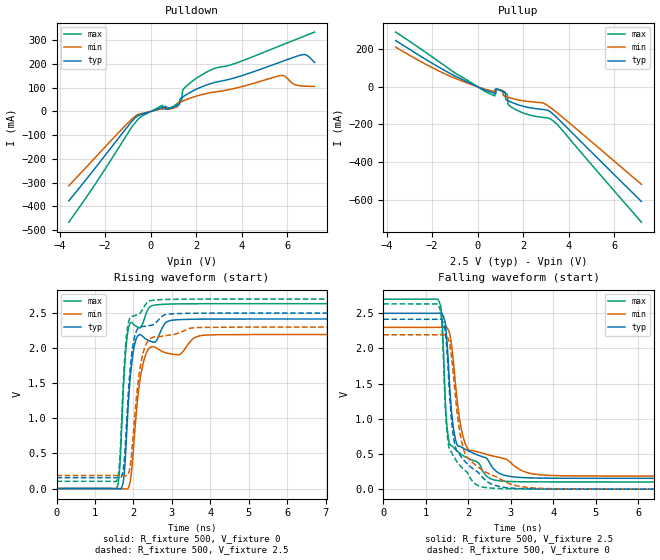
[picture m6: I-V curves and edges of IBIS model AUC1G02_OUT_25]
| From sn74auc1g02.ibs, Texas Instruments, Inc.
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[Model]   AUC1G02_OUT_25
Model_type  Output
Vref =   0
Rref =   500
Cref =   30p
Vmeas =   1.25
| variable   typ   min   max
C_comp   4.93pF   0.39pF   11.12pF
| C_pullup   5.22pF   0.39pF   11.12pF
| C_pulldown   4.64pF   0.40pF   6.60pF
[Temperature Range]   40   100   -40
| Ambient temperature   25   85   -40
[Voltage range]   2.5   2.3   2.7
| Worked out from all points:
|   slope of the pulldown table from 0 to 0.375 V, typ, clamps not added: 30.9 ohm
|   slope of the pullup table from 0 to 0.375 V, typ, clamps not added: 19.1 ohm
|   rising waveform, R_fixture 500, V_fixture 0: 20-80 % time 196ps typ, 259ps min, 158ps max; typ from 0 V to 2.42 V
|   falling waveform, R_fixture 500, V_fixture 2.5: 20-80 % time 237ps typ, 315ps min, 197ps max; typ from 2.5 V to 0.154 V
|   rising waveform, R_fixture 500, V_fixture 2.5: 20-80 % time 194ps typ, 257ps min, 157ps max; typ from 0.154 V to 2.5 V
|   falling waveform, R_fixture 500, V_fixture 0: 20-80 % time 304ps typ, 370ps min, 202ps max; typ from 2.42 V to 0 V
[Pulldown]
| AUC1G02_OUT_25
|   Voltage   I(typ)   I(min)   I(max)
-3.6V     -377.3mA   -313.6mA   -467.3mA
-450mV    -13.55mA   -9.199mA   -23.42mA
515mV     17.02mA    12.57mA    25.99mA
1.025V    18.9mA     15.4mA     23.61mA
1.27V     30.1mA     38.43mA    41.47mA
1.37V     59.42mA    42.49mA    49.07mA
1.395V    60.94mA    43.5mA     85.27mA
1.48V     66.06mA    46.86mA    98.94mA
2.54V     114.8mA    77.9mA     170.7mA
5.695V    208.5mA    151.4mA    277.9mA
6.74V     240.5mA    107.1mA    317.9mA
7.2V      207mA      105.8mA    335.2mA
[Pullup]
| AUC1G02_OUT_25
|   Voltage   I(typ)   I(min)   I(max)
-3.6V     246.2mA    211mA      291.3mA
290mV     -15.56mA   -11.38mA   -21.64mA
750mV     -34.5mA    -24.9mA    -48.13mA
770mV     -35.18mA   -25.36mA   -13.07mA
1.115V    -23.95mA   -20.34mA   -27.78mA
1.215V    -28.93mA   -50.57mA   -34.8mA
1.235V    -63.85mA   -51.41mA   -36.2mA
1.295V    -71.17mA   -53.86mA   -40.35mA
1.34V     -74.13mA   -55.63mA   -92.46mA
1.59V     -87.28mA   -64.24mA   -115.7mA
3.28V     -141.4mA   -117.9mA   -177.8mA
7.2V      -610.5mA   -519.3mA   -720.6mA
[Ramp]
| AUC1G02_OUT_25
| variable   typ   min   max
dV/dt_r   1.46/1.99E-10   1.32/2.61E-10   1.58/1.59E-10
dV/dt_f   1.41/2.39E-10   1.28/3.16E-10   1.56/1.98E-10
R_load = 500
[Rising Waveform]
| AUC1G02_OUT_25
R_fixture =   500
C_fixture =   0
L_fixture =   0
V_fixture =   0
V_fixture_min = 0
V_fixture_max = 0
|   Time   V(typ)   V(min)   V(max)
0s        8.552nV    24.69nV    1.796nV
1.56ns    -2.155mV   -44.43uV   506.3uV
1.64ns    -6.797mV   -188.6uV   261mV
1.735ns   92.22mV    -3.3mV     1.391V
1.87ns    1.234V     13.09mV    2.281V
2.08ns    2.143V     1.114V     2.309V
2.275ns   2.151V     1.833V     2.404V
2.525ns   2.085V     2.021V     2.612V
3.345ns   2.41V      1.996V     2.633V
24.99ns   2.416V     2.195V     2.634V
[Falling Waveform]
| AUC1G02_OUT_25
R_fixture =   500
C_fixture =   0
L_fixture =   0
V_fixture =   2.5
V_fixture_min = 2.3
V_fixture_max = 2.7
|   Time   V(typ)   V(min)   V(max)
0s        2.5V       2.3V       2.7V
1.285ns   2.501V     2.3V       2.699V
1.38ns    2.497V     2.303V     2.421V
1.455ns   2.372V     2.312V     1.314V
1.555ns   1.53V      2.226V     648.9mV
1.695ns   717.2mV    1.516V     564.8mV
1.93ns    567.5mV    643.2mV    458.7mV
2.67ns    248.5mV    458.6mV    124.1mV
4.21ns    155.1mV    190.2mV    102.8mV
24.99ns   154.5mV    186.3mV    102.6mV
[Rising Waveform]
| AUC1G02_OUT_25
R_fixture =   500
C_fixture =   0
L_fixture =   0
V_fixture =   2.5
V_fixture_min = 2.3
V_fixture_max = 2.7
|   Time   V(typ)   V(min)   V(max)
0s        154.5mV    186.3mV    102.6mV
1.56ns    153mV      186.3mV    104.4mV
1.64ns    149.6mV    186.2mV    380.2mV
1.73ns    246.1mV    184.2mV    1.436V
1.86ns    1.304V     198.6mV    2.334V
1.935ns   1.817V     400.4mV    2.449V
2.05ns    2.204V     1.136V     2.467V
2.23ns    2.308V     1.884V     2.544V
2.45ns    2.325V     2.142V     2.678V
24.99ns   2.5V       2.3V       2.7V
[Falling Waveform]
| AUC1G02_OUT_25
R_fixture =   500
C_fixture =   0
L_fixture =   0
V_fixture =   0
V_fixture_min = 0
V_fixture_max = 0
|   Time   V(typ)   V(min)   V(max)
0s        2.416V     2.195V     2.634V
1.285ns   2.415V     2.195V     2.629V
1.38ns    2.405V     2.195V     2.329V
1.455ns   2.26V      2.196V     1.21V
1.545ns   1.482V     2.105V     595.5mV
1.675ns   661.2mV    1.452V     445mV
1.875ns   427.7mV    597.5mV    292.3mV
2.365ns   148.9mV    259.4mV    27.2mV
4.11ns    726.1uV    4.32mV     171uV
24.99ns   17.46uV    1.178uV    8.082uV
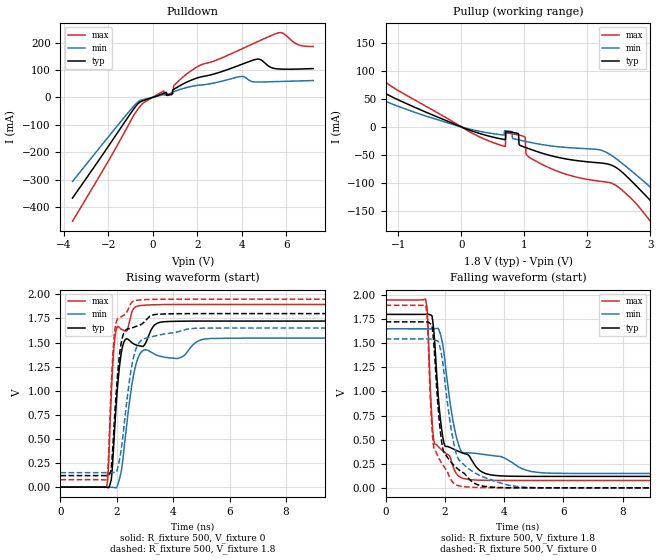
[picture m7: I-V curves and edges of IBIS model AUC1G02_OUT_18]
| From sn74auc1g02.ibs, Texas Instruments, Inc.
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[Model]   AUC1G02_OUT_18
Model_type  Output
Vref =   0
Rref =   1000
Cref =   30p
Vmeas =   0.9
| variable   typ   min   max
C_comp   5.30pF   0.57pF   7.93pF
| C_pullup   4.83pF   0.57pF   7.93pF
| C_pulldown   5.78pF   2.98pF   7.79pF
[Temperature Range]   40   100   -40
| Ambient temperature   25   85   -40
[Voltage range]   1.8   1.65   1.95
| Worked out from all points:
|   slope of the pulldown table from 0 to 0.27 V, typ, clamps not added: 34.4 ohm
|   slope of the pullup table from 0 to 0.27 V, typ, clamps not added: 24.6 ohm
|   rising waveform, R_fixture 500, V_fixture 0: 20-80 % time 279ps typ, 424ps min, 192ps max; typ from 0 V to 1.72 V
|   falling waveform, R_fixture 500, V_fixture 1.8: 20-80 % time 311ps typ, 471ps min, 253ps max; typ from 1.8 V to 0.119 V
|   rising waveform, R_fixture 500, V_fixture 1.8: 20-80 % time 271ps typ, 411ps min, 185ps max; typ from 0.119 V to 1.8 V
|   falling waveform, R_fixture 500, V_fixture 0: 20-80 % time 374ps typ, 486ps min, 249ps max; typ from 1.72 V to 0 V
[Pulldown]
| AUC1G02_OUT_18
|   Voltage   I(typ)   I(min)   I(max)
-3.6V     -367.3mA   -306.5mA   -451.8mA
-840mV    -41.05mA   -31.3mA    -64.3mA
-415mV    -11.62mA   -7.635mA   -20.14mA
495mV     14.95mA    10.62mA    23.51mA
885mV     12.29mA    19.09mA    15.87mA
925mV     28.57mA    20.19mA    16.9mA
960mV     30.15mA    21.18mA    44.34mA
2.04V     71.84mA    43.97mA    113.3mA
3.92V     118.2mA    75.81mA    173.7mA
4.62V     138.3mA    55.96mA    199.9mA
5.58V     103.9mA    57.6mA     233.8mA
7.2V      105mA      61.31mA    185.3mA
[Pullup]
| AUC1G02_OUT_18
|   Voltage   I(typ)   I(min)   I(max)
-3.6V     220.3mA    181.9mA    264.7mA
-2.44V    138.5mA    110.5mA    175.8mA
180mV     -7.622mA   -5.122mA   -11.6mA
695mV     -22.64mA   -6.828mA   -34.84mA
705mV     -8.169mA   -6.943mA   -10.57mA
905mV     -11.83mA   -22.82mA   -14.13mA
970mV     -34.54mA   -24.44mA   -16.12mA
1.11V     -40.27mA   -27.85mA   -56.21mA
2.24V     -64.51mA   -42.18mA   -97.18mA
3.135V    -146.9mA   -120.3mA   -187.2mA
3.975V    -247.4mA   -204.7mA   -306.6mA
7.2V      -630.7mA   -535mA     -754.9mA
[Ramp]
| AUC1G02_OUT_18
| variable   typ   min   max
dV/dt_r   1.04/2.81E-10   0.93/4.33E-10   1.14/1.94E-10
dV/dt_f   1.01/3.13E-10   0.90/4.79E-10   1.13/2.47E-10
R_load = 500
[Rising Waveform]
| AUC1G02_OUT_18
R_fixture =   500
C_fixture =   0
L_fixture =   0
V_fixture =   0
V_fixture_min = 0
V_fixture_max = 0
|   Time   V(typ)   V(min)   V(max)
0s        6.473nV    21.42nV    1.057nV
1.635ns   -1.692mV   272uV      -213.1uV
1.7ns     -7.353mV   395.4uV    191.9mV
1.805ns   81.56mV    -1.199mV   973.5mV
1.955ns   758.2mV    -6.809mV   1.6V
2.23ns    1.488V     327.3mV    1.627V
2.735ns   1.47V      1.327V     1.878V
3.865ns   1.718V     1.341V     1.894V
5.365ns   1.722V     1.542V     1.895V
24.99ns   1.722V     1.546V     1.894V
[Falling Waveform]
| AUC1G02_OUT_18
R_fixture =   500
C_fixture =   0
L_fixture =   0
V_fixture =   1.8
V_fixture_min = 1.65
V_fixture_max = 1.95
|   Time   V(typ)   V(min)   V(max)
0s        1.8V       1.65V      1.95V
1.345ns   1.801V     1.65V      1.956V
1.405ns   1.802V     1.65V      1.828V
1.535ns   1.792V     1.65V      859.6mV
1.64ns    1.576V     1.651V     464.7mV
1.97ns    463mV      1.395V     372.7mV
2.315ns   398.8mV    628.6mV    189.2mV
2.65ns    356mV      363.1mV    95.62mV
4.035ns   122.2mV    306.9mV    76.53mV
24.99ns   118.7mV    149.7mV    76.31mV
[Rising Waveform]
| AUC1G02_OUT_18
R_fixture =   500
C_fixture =   0
L_fixture =   0
V_fixture =   1.8
V_fixture_min = 1.65
V_fixture_max = 1.95
|   Time   V(typ)   V(min)   V(max)
0s        118.7mV    149.7mV    76.3mV
1.635ns   117.5mV    149.8mV    78.99mV
1.695ns   118.2mV    149.9mV    258.2mV
1.79ns    172.4mV    150.6mV    969.7mV
1.945ns   842.8mV    153.5mV    1.663V
2.19ns    1.545V     466.1mV    1.773V
2.45ns    1.645V     1.111V     1.877V
2.645ns   1.663V     1.406V     1.935V
4.8ns     1.8V       1.648V     1.95V
24.99ns   1.8V       1.65V      1.95V
[Falling Waveform]
| AUC1G02_OUT_18
R_fixture =   500
C_fixture =   0
L_fixture =   0
V_fixture =   0
V_fixture_min = 0
V_fixture_max = 0
|   Time   V(typ)   V(min)   V(max)
0s        1.722V     1.546V     1.894V
1.345ns   1.722V     1.545V     1.894V
1.405ns   1.722V     1.545V     1.754V
1.525ns   1.7V       1.544V     825mV
1.62ns    1.516V     1.538V     426.8mV
1.925ns   412.6mV    1.304V     239.5mV
2.225ns   260.7mV    587.3mV    74.68mV
2.485ns   184.2mV    287.1mV    19.95mV
4.825ns   219.2uV    4.962mV    -80.61uV
24.99ns   20.57uV    2.16uV     9.128uV
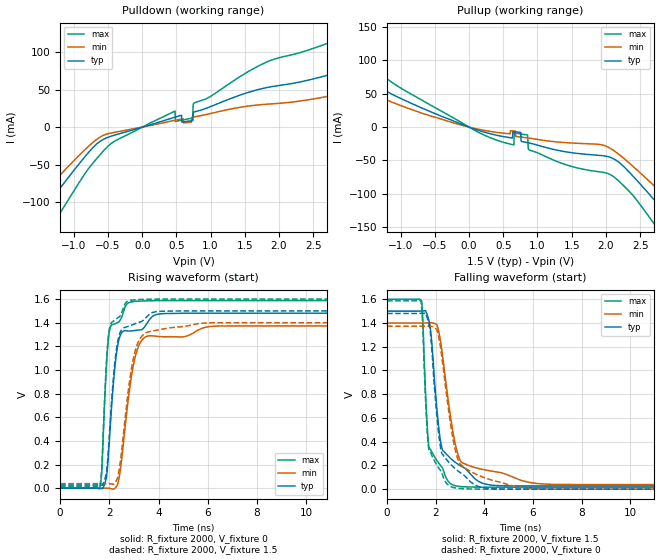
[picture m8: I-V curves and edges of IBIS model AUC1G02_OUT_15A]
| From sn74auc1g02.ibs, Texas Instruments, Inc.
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[Model]   AUC1G02_OUT_15A
Model_type  Output
Vref =   0
Rref =   2000
Cref =   15p
Vmeas =   0.75
| variable   typ   min   max
C_comp   6.58pF   0.06pF   14.96pF
| C_pullup   4.77pF   0.06pF   9.14pF
| C_pulldown   8.38pF   2.09pF   14.96pF
[Temperature Range]   40   100   -40
| Ambient temperature   25   85   -40
[Voltage range]   1.5   1.4   1.6
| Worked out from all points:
|   slope of the pulldown table from 0 to 0.225 V, typ, clamps not added: 36.6 ohm
|   slope of the pullup table from 0 to 0.225 V, typ, clamps not added: 29.5 ohm
|   rising waveform, R_fixture 2000, V_fixture 0: 20-80 % time 355ps typ, 520ps min, 237ps max; typ from 0 V to 1.48 V
|   falling waveform, R_fixture 2000, V_fixture 1.5: 20-80 % time 455ps typ, 607ps min, 287ps max; typ from 1.5 V to 0.027 V
|   rising waveform, R_fixture 2000, V_fixture 1.5: 20-80 % time 351ps typ, 512ps min, 234ps max; typ from 0.027 V to 1.5 V
|   falling waveform, R_fixture 2000, V_fixture 0: 20-80 % time 428ps typ, 615ps min, 282ps max; typ from 1.48 V to 0 V
[Pulldown]
| AUC1G02_OUT_15A
|   Voltage   I(typ)   I(min)   I(max)
-3.6V     -362.7mA   -303.6mA   -444.4mA
-2.14V    -192.5mA   -156.8mA   -246.4mA
-1.825V   -155.4mA   -125.4mA   -203.1mA
-1.36V    -100.2mA   -79.41mA   -137.7mA
-405mV    -10.71mA   -6.927mA   -18.81mA
480mV     13.33mA    9.224mA    21.44mA
485mV     13.46mA    9.315mA    7.619mA
735mV     8.725mA    13.4mA     12.06mA
755mV     20.22mA    13.7mA     32.02mA
1.69V     50.1mA     29.63mA    81.31mA
3.34V     86.08mA    49.9mA     134.3mA
7.2V      80.61mA    45.5mA     141.2mA
[Pullup]
| AUC1G02_OUT_15A
|   Voltage   I(typ)   I(min)   I(max)
-3.6V     206.9mA    155.1mA    250.9mA
-2.745V   148.8mA    117.7mA    187.1mA
-2.3V     119.4mA    93.54mA    153.8mA
115mV     -4.163mA   -2.727mA   -6.621mA
650mV     -6.722mA   -5.655mA   -26.6mA
660mV     -6.84mA    -5.748mA   -8.817mA
855mV     -23.23mA   -16.19mA   -11.7mA
885mV     -23.9mA    -16.64mA   -34.51mA
2.09V     -46.33mA   -33.4mA    -72.65mA
2.735V    -112.2mA   -90.7mA    -149.1mA
3.355V    -185.6mA   -151.9mA   -237.2mA
7.2V      -640.7mA   -543.6mA   -770.5mA
[Ramp]
| AUC1G02_OUT_15A
| variable   typ   min   max
dV/dt_r   0.89/3.58E-10   0.83/5.26E-10   0.96/2.39E-10
dV/dt_f   0.89/4.77E-10   0.82/6.11E-10   0.95/2.87E-10
R_load = 2000
[Rising Waveform]
| AUC1G02_OUT_15A
R_fixture =   2000
C_fixture =   0
L_fixture =   0
V_fixture =   0
V_fixture_min = 0
V_fixture_max = 0
|   Time   V(typ)   V(min)   V(max)
0s        6.138nV    22.63nV    845.8pV
1.605ns   -1.237mV   80.59uV    -4.897mV
1.69ns    -2.471mV   119uV      141.4mV
1.885ns   95.51mV    231.7uV    1.049V
1.995ns   386.2mV    99.07uV    1.318V
2.345ns   1.214V     38.89mV    1.402V
2.835ns   1.33V      859.3mV    1.573V
3.41ns    1.359V     1.271V     1.584V
6.105ns   1.481V     1.368V     1.587V
24.99ns   1.481V     1.373V     1.587V
[Falling Waveform]
| AUC1G02_OUT_15A
R_fixture =   2000
C_fixture =   0
L_fixture =   0
V_fixture =   1.5
V_fixture_min = 1.4
V_fixture_max = 1.6
|   Time   V(typ)   V(min)   V(max)
0s        1.5V       1.4V       1.6V
1.42ns    1.502V     1.4V       1.587V
1.62ns    1.487V     1.401V     652.2mV
1.725ns   1.417V     1.402V     353mV
2.045ns   684.3mV    1.387V     243.1mV
2.21ns    391.2mV    1.232V     196.7mV
2.745ns   235.9mV    440.2mV    32.49mV
3.095ns   188.6mV    221.6mV    20.71mV
6.18ns    27.16mV    47.24mV    16.43mV
24.99ns   27.2mV     38.78mV    16.41mV
[Rising Waveform]
| AUC1G02_OUT_15A
R_fixture =   2000
C_fixture =   0
L_fixture =   0
V_fixture =   1.5
V_fixture_min = 1.4
V_fixture_max = 1.6
|   Time   V(typ)   V(min)   V(max)
0s        27.17mV    38.78mV    16.4mV
1.605ns   26.31mV    38.84mV    12.35mV
1.69ns    25.44mV    38.88mV    164.3mV
1.885ns   138.1mV    38.98mV    1.077V
1.995ns   435.6mV    38.91mV    1.339V
2.325ns   1.225V     82.87mV    1.439V
2.81ns    1.372V     888.6mV    1.587V
3.385ns   1.422V     1.3V       1.597V
5.68ns    1.5V       1.394V     1.6V
24.99ns   1.5V       1.4V       1.6V
[Falling Waveform]
| AUC1G02_OUT_15A
R_fixture =   2000
C_fixture =   0
L_fixture =   0
V_fixture =   0
V_fixture_min = 0
V_fixture_max = 0
|   Time   V(typ)   V(min)   V(max)
0s        1.481V     1.373V     1.587V
1.39ns    1.481V     1.373V     1.591V
1.62ns    1.463V     1.373V     598.4mV
1.71ns    1.398V     1.373V     343.8mV
2.045ns   623mV      1.345V     203.6mV
2.2ns     348.2mV    1.192V     156.8mV
2.7ns     191.9mV    436.3mV    15.5mV
3.24ns    102.4mV    174.6mV    2.696mV
5.685ns   115.9uV    9.469mV    3.293uV
24.99ns   24.12uV    3.304uV    10.3uV
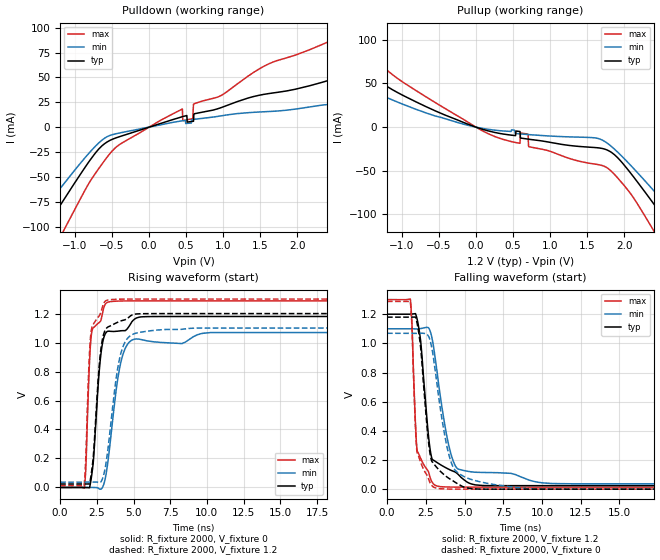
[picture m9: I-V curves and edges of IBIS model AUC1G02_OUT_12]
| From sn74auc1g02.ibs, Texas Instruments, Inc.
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[Model]   AUC1G02_OUT_12
Model_type  Output
Vref =   0
Rref =   2000
Cref =   15p
Vmeas =   0.6
| variable   typ   min   max
C_comp   8.58pF   0.77pF   20.74pF
| C_pullup   6.20pF   0.77pF   15.62pF
| C_pulldown   10.96pF   4.26pF   20.74pF
[Temperature Range]   40   100   -40
| Ambient temperature   25   85   -40
[Voltage range]   1.2   1.1   1.3
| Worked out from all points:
|   slope of the pulldown table from 0 to 0.18 V, typ, clamps not added: 41.7 ohm
|   slope of the pullup table from 0 to 0.18 V, typ, clamps not added: 39.1 ohm
|   rising waveform, R_fixture 2000, V_fixture 0: 20-80 % time 505ps typ, 818ps min, 307ps max; typ from 0 V to 1.18 V
|   falling waveform, R_fixture 2000, V_fixture 1.2: 20-80 % time 587ps typ, 980ps min, 296ps max; typ from 1.2 V to 0.024 V
|   rising waveform, R_fixture 2000, V_fixture 1.2: 20-80 % time 498ps typ, 809ps min, 305ps max; typ from 0.024 V to 1.2 V
|   falling waveform, R_fixture 2000, V_fixture 0: 20-80 % time 593ps typ, 995ps min, 298ps max; typ from 1.18 V to 0 V
[Pulldown]
| AUC1G02_OUT_12
|   Voltage   I(typ)   I(min)   I(max)
-3.6V     -358.1mA   -300.1mA   -438mA
-1.74V    -141.6mA   -114.1mA   -185.6mA
-1.425V   -104.9mA   -83.3mA    -142.2mA
-1.205V   -79.25mA   -62.17mA   -111.4mA
-680mV    -22.07mA   -15.95mA   -41.78mA
-400mV    -9.617mA   -5.913mA   -17.55mA
450mV     10.5mA     6.398mA    18.24mA
590mV     5.848mA    7.731mA    8.546mA
605mV     12.96mA    7.861mA    23.36mA
2.86V     55.95mA    19.1mA     100.7mA
3.425V    44.58mA    20.08mA    119.3mA
7.2V      57.06mA    26.83mA    108mA
[Pullup]
| AUC1G02_OUT_12
|   Voltage   I(typ)   I(min)   I(max)
-3.6V     177mA      42.66mA    237.7mA
-2.43V    116.1mA    56.06mA    152.8mA
-1.99V    89.76mA    64.98mA    121mA
85mV      -2.357mA   -1.386mA   -4.118mA
595mV     -5.009mA   -7.72mA    -18.47mA
700mV     -13.68mA   -8.451mA   -7.891mA
720mV     -13.91mA   -8.58mA    -22.52mA
1.785V    -26.75mA   -19.14mA   -47.45mA
2.43V     -91.29mA   -75.54mA   -122.8mA
2.73V     -126.3mA   -104.6mA   -165.3mA
3.085V    -168.1mA   -139.6mA   -215.3mA
7.2V      -652.5mA   -556.7mA   -783.9mA
[Ramp]
| AUC1G02_OUT_12
| variable   typ   min   max
dV/dt_r   0.71/5.13E-10   0.65/8.28E-10   0.78/3.16E-10
dV/dt_f   0.71/5.97E-10   0.64/9.93E-10   0.77/3.02E-10
R_load = 2000
[Rising Waveform]
| AUC1G02_OUT_12
R_fixture =   2000
C_fixture =   0
L_fixture =   0
V_fixture =   0
V_fixture_min = 0
V_fixture_max = 0
|   Time   V(typ)   V(min)   V(max)
0s        5.734nV    24nV       679.7pV
1.645ns   -283uV     29.88uV    -5.88mV
1.755ns   -662.1uV   72.95uV    146.5mV
2.005ns   -712uV     207.6uV    873.7mV
2.185ns   111.7mV    -44.86uV   1.087V
2.755ns   901.2mV    -11.81mV   1.148V
3.185ns   1.075V     127.7mV    1.276V
4.07ns    1.08V      832.8mV    1.286V
4.95ns    1.151V     1.02V      1.287V
24.99ns   1.18V      1.069V     1.287V
[Falling Waveform]
| AUC1G02_OUT_12
R_fixture =   2000
C_fixture =   0
L_fixture =   0
V_fixture =   1.2
V_fixture_min = 1.1
V_fixture_max = 1.3
|   Time   V(typ)   V(min)   V(max)
0s        1.2V       1.1V       1.3V
1.505ns   1.2V       1.1V       1.304V
1.605ns   1.201V     1.1V       1.143V
1.94ns    1.167V     1.099V     266.7mV
2.17ns    1.016V     1.101V     211.3mV
2.755ns   292.2mV    1.092V     88.1mV
3.155ns   187.8mV    863.2mV    24.34mV
3.92ns    139.9mV    331.6mV    14.86mV
4.6ns     100.6mV    137.1mV    13.99mV
24.99ns   24.01mV    36.66mV    13.87mV
[Rising Waveform]
| AUC1G02_OUT_12
R_fixture =   2000
C_fixture =   0
L_fixture =   0
V_fixture =   1.2
V_fixture_min = 1.1
V_fixture_max = 1.3
|   Time   V(typ)   V(min)   V(max)
0s        23.98mV    36.64mV    13.86mV
1.63ns    24.02mV    36.66mV    10.25mV
1.745ns   24.01mV    36.68mV    202.8mV
2.005ns   25.2mV     36.76mV    938.6mV
2.255ns   208.3mV    36.92mV    1.125V
2.73ns    914mV      34.27mV    1.197V
3.13ns    1.095V     171.1mV    1.289V
4.035ns   1.145V     882.5mV    1.299V
4.995ns   1.193V     1.059V     1.3V
24.99ns   1.2V       1.1V       1.3V
[Falling Waveform]
| AUC1G02_OUT_12
R_fixture =   2000
C_fixture =   0
L_fixture =   0
V_fixture =   0
V_fixture_min = 0
V_fixture_max = 0
|   Time   V(typ)   V(min)   V(max)
0s        1.18V      1.069V     1.287V
1.505ns   1.18V      1.069V     1.287V
1.605ns   1.18V      1.069V     1.118V
1.925ns   1.145V     1.068V     262.5mV
2.17ns    970.7mV    1.069V     184.2mV
2.71ns    293.4mV    1.042V     61.13mV
3.045ns   170.3mV    864mV      11.97mV
4.07ns    68.82mV    206.7mV    594.8uV
5.275ns   6.038mV    72.25mV    -12.3uV
24.99ns   29.36uV    6.821uV    11.39uV
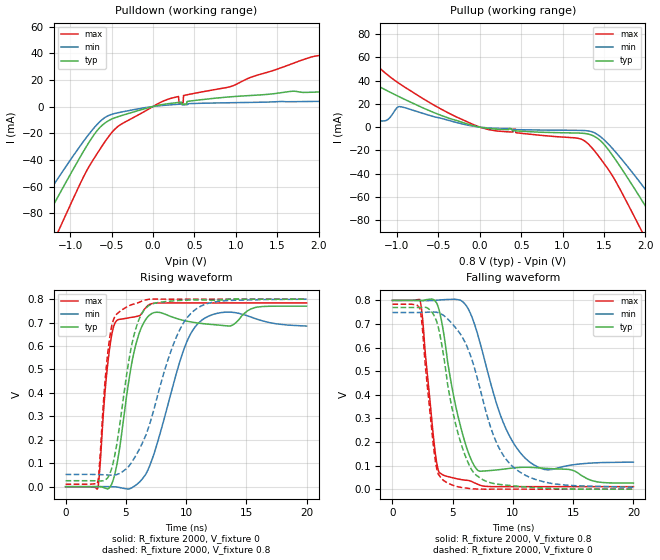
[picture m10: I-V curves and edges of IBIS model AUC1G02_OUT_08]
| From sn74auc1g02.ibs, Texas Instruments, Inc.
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[Model]   AUC1G02_OUT_08
Model_type  Output
Vref =   0
Rref =   2000
Cref =   15p
Vmeas =   0.4
| variable   typ   min   max
C_comp   11.54pF   4.32pF   28.22pF
| C_pullup   9.97pF   4.32pF   19.92pF
| C_pulldown   13.10pF   5.60pF   28.22pF
[Temperature Range]   40   100   -40
| Ambient temperature   25   85   -40
[Voltage range]   0.8   0.8   0.8
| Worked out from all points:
|   slope of the pulldown table from 0 to 0.12 V, typ, clamps not added: 77.1 ohm
|   slope of the pullup table from 0 to 0.12 V, typ, clamps not added: 92.3 ohm
|   rising waveform, R_fixture 2000, V_fixture 0: 20-80 % time 1.43ns typ, 2.26ns min, 817ps max; typ from 0 V to 0.77 V
|   falling waveform, R_fixture 2000, V_fixture 0.8: 20-80 % time 1.83ns typ, 2.43ns min, 893ps max; typ from 0.8 V to 0.026 V
|   rising waveform, R_fixture 2000, V_fixture 0.8: 20-80 % time 1.43ns typ, 2.79ns min, 768ps max; typ from 0.025 V to 0.8 V
|   falling waveform, R_fixture 2000, V_fixture 0: 20-80 % time 1.87ns typ, 2.83ns min, 893ps max; typ from 0.77 V to 0 V
[Pulldown]
| AUC1G02_OUT_08
|   Voltage   I(typ)   I(min)   I(max)
-3.6V     -351.9mA   -296.5mA   -427.3mA
-1.64V    -124.3mA   -101.1mA   -161.8mA
-1.505V   -108.7mA   -87.99mA   -143.3mA
-1.38V    -94.32mA   -75.96mA   -126.2mA
-1.16V    -69.17mA   -55.13mA   -96mA
-645mV    -16.01mA   -11.6mA    -32.55mA
-435mV    -7.893mA   -4.858mA   -15.6mA
-95mV     -1.581mA   -843.7uA   -3.47mA
210mV     2.329mA    1.254mA    6.027mA
1.98V     10.84mA    3.867mA    38.03mA
2.365V    11.74mA    4.199mA    33.49mA
7.2V      23.85mA    8.894mA    59.34mA
[Pullup]
| AUC1G02_OUT_08
|   Voltage   I(typ)   I(min)   I(max)
-3.6V     29.03mA    5.564mA    125.2mA
-1.765V   22.08mA    5.736mA    86.24mA
-1.295V   37.05mA    6.079mA    56.15mA
-1.125V   31.49mA    5.855mA    45.5mA
-970mV    25.97mA    17.63mA    37.33mA
-280mV    5.688mA    3.931mA    8.662mA
1.31V     -5.923mA   -3.24mA    -14.41mA
1.515V    -16.04mA   -11.83mA   -32.61mA
1.89V     -55.22mA   -43.27mA   -80.15mA
2.125V    -81.9mA    -65.14mA   -112.8mA
2.4V      -113.7mA   -91.48mA   -151.1mA
7.2V      -673.4mA   -574.2mA   -807.7mA
[Ramp]
| AUC1G02_OUT_08
| variable   typ   min   max
dV/dt_r   0.47/1.46E-09   0.45/2.57E-09   0.48/8.27E-10
dV/dt_f   0.47/1.87E-09   0.43/2.67E-09   0.48/9.05E-10
R_load = 2000
[Rising Waveform]
| AUC1G02_OUT_08
R_fixture =   2000
C_fixture =   0
L_fixture =   0
V_fixture =   0
V_fixture_min = 0
V_fixture_max = 0
|   Time   V(typ)   V(min)   V(max)
0s        7.013nV    39.16nV    506.9pV
2.665ns   487.3uV    414.1uV    -6.744mV
3.53ns    -8.83mV    394.1uV    537.4mV
4.275ns   99.13mV    -1.636mV   709.9mV
5.665ns   570.4mV    776.1uV    723.6mV
6.975ns   732.3mV    87.96mV    777.6mV
9.705ns   710.3mV    569.1mV    783.6mV
11.09ns   697.4mV    700.7mV    783.6mV
13.62ns   685.1mV    744.5mV    783.7mV
20ns      769.9mV    685mV      783.7mV
[Falling Waveform]
| AUC1G02_OUT_08
R_fixture =   2000
C_fixture =   0
L_fixture =   0
V_fixture =   0.8
V_fixture_min = 0.8
V_fixture_max = 0.8
|   Time   V(typ)   V(min)   V(max)
0s        800mV      800mV      800mV
2.28ns    799.6mV    799.8mV    802.4mV
3.46ns    801.1mV    799.9mV    195.2mV
3.915ns   750.4mV    801.8mV    68.81mV
5.445ns   308.4mV    803mV      43.09mV
6.255ns   161.7mV    767.4mV    37.26mV
7.08ns    79.83mV    654.9mV    20.85mV
9.175ns   84.58mV    285.5mV    10.65mV
11.3ns    92.68mV    118.7mV    10.65mV
20ns      25.77mV    114.7mV    10.62mV
[Rising Waveform]
| AUC1G02_OUT_08
R_fixture =   2000
C_fixture =   0
L_fixture =   0
V_fixture =   0.8
V_fixture_min = 0.8
V_fixture_max = 0.8
|   Time   V(typ)   V(min)   V(max)
0s        25.46mV    52.25mV    10.6mV
2.645ns   25.18mV    52.1mV     15.29mV
3.6ns     47.57mV    49.5mV     612.3mV
3.94ns    99.98mV    49.66mV    706.4mV
4.46ns    251.7mV    56.05mV    745.7mV
5.62ns    633.8mV    114.7mV    778.4mV
6.87ns    771mV      249.7mV    799mV
8.965ns   792.7mV    609mV      799.8mV
10.62ns   796.6mV    749.4mV    799.9mV
20ns      799.9mV    799.4mV    800mV
[Falling Waveform]
| AUC1G02_OUT_08
R_fixture =   2000
C_fixture =   0
L_fixture =   0
V_fixture =   0
V_fixture_min = 0
V_fixture_max = 0
|   Time   V(typ)   V(min)   V(max)
0s        770mV      748.6mV    783.8mV
2.27ns    769.9mV    748.7mV    767.1mV
3.56ns    724.3mV    750.3mV    120.6mV
4.28ns    554.4mV    734.8mV    35.67mV
4.87ns    362.7mV    706.2mV    19.56mV
5.65ns    200.4mV    656.7mV    7.91mV
7.285ns   46.78mV    422.9mV    229.5uV
8.76ns    20.94mV    183.8mV    87.36uV
10.58ns   11.32mV    72.34mV    56.39uV
20ns      105.3uV    7.985mV    22.98uV
